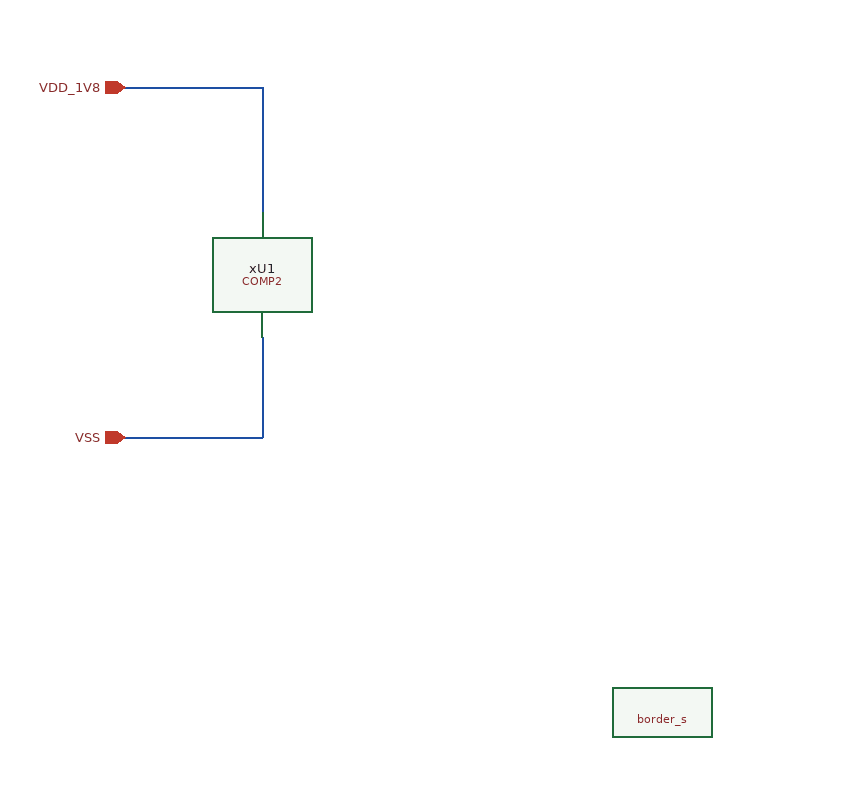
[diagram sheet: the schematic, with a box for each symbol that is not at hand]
v {xschem version=3.4.6 file_version=1.2}
G {}
K {}
V {}
S {}
E {}
N 100 -500 210 -500 {lab=VDD_1V8}
N 210 -500 210 -400 {lab=VDD_1V8}
N 100 -220 210 -220 {lab=VSS}
N 210 -300 210 -220 {lab=VSS}
C {cborder/border_s.sym} 530 0 0 0 {
user="Carsten Wulff"
company="Wulff Consulting AS"}
C {devices/ipin.sym} 100 -500 0 0 {name=p1 lab=VDD_1V8}
C {devices/ipin.sym} 100 -220 0 0 {name=p2 lab=VSS}
C {LELO_BKLE_IHP13G2/COMP2.sym} 90 -450 0 0 {name=xU1}
